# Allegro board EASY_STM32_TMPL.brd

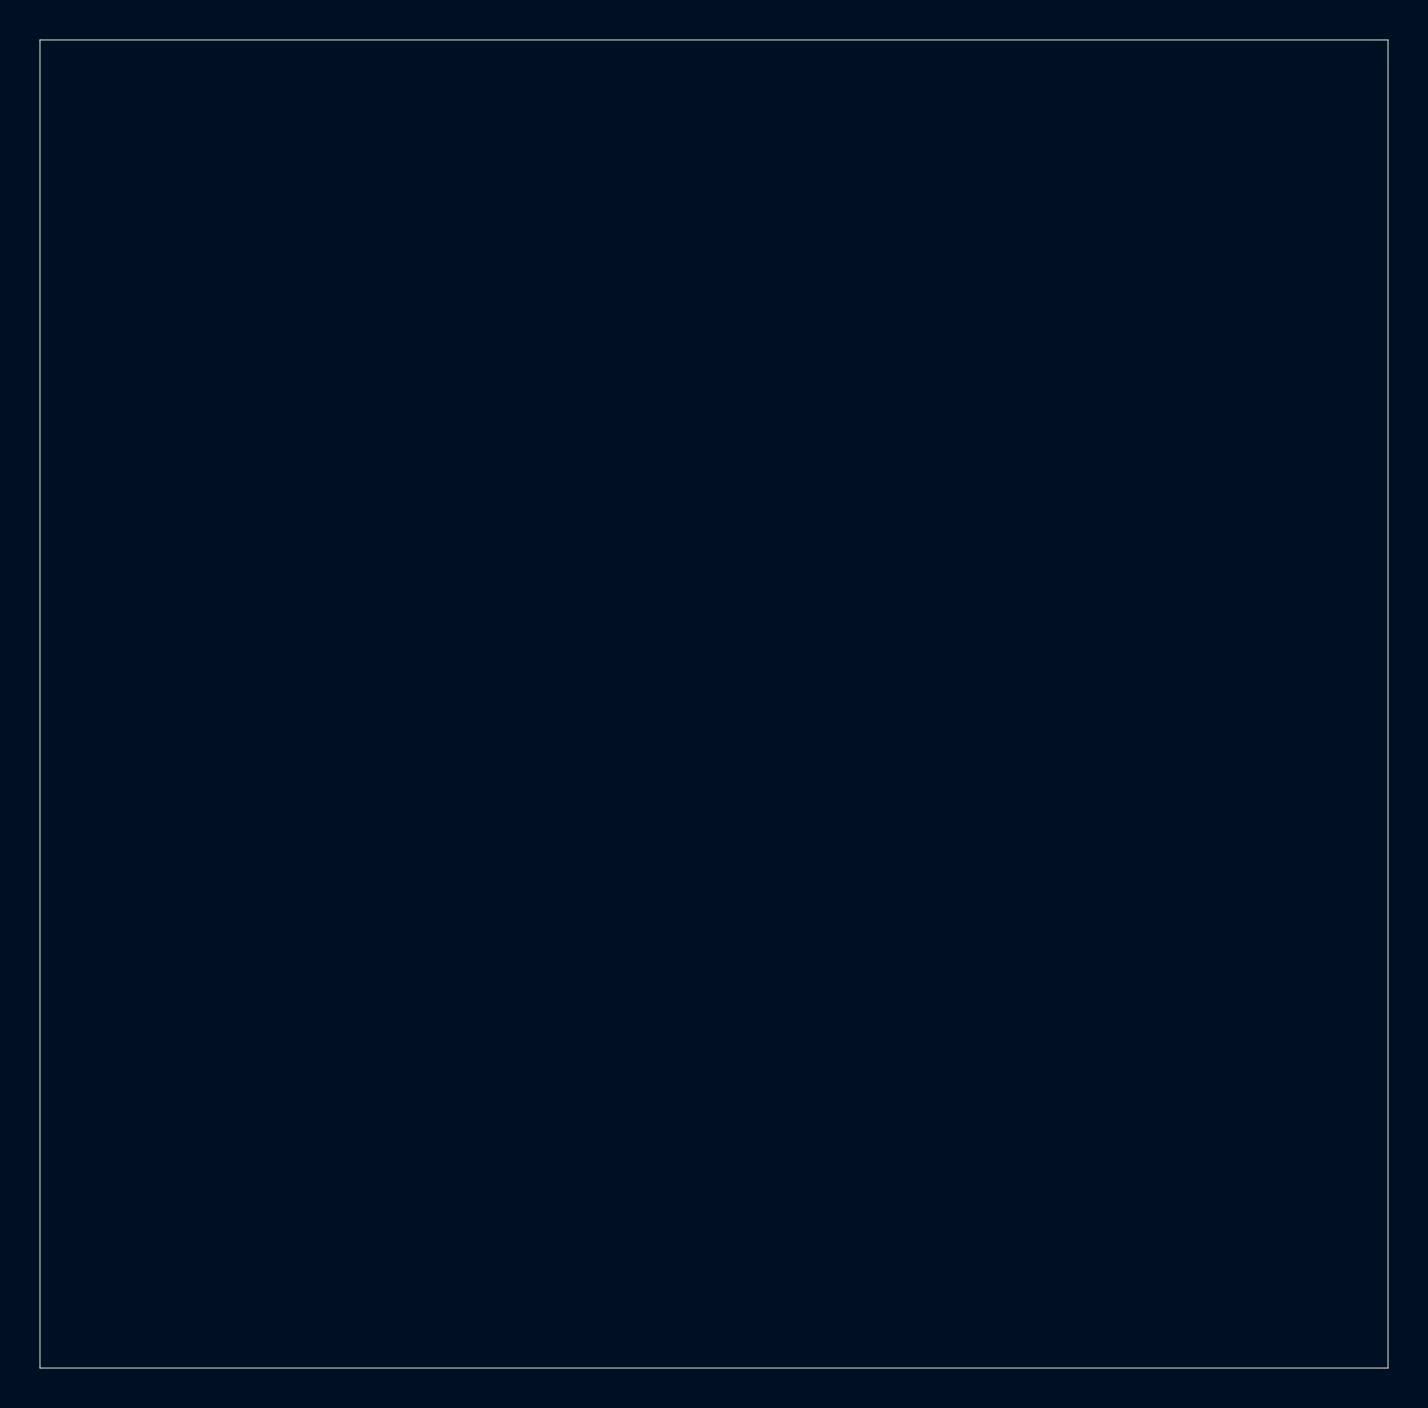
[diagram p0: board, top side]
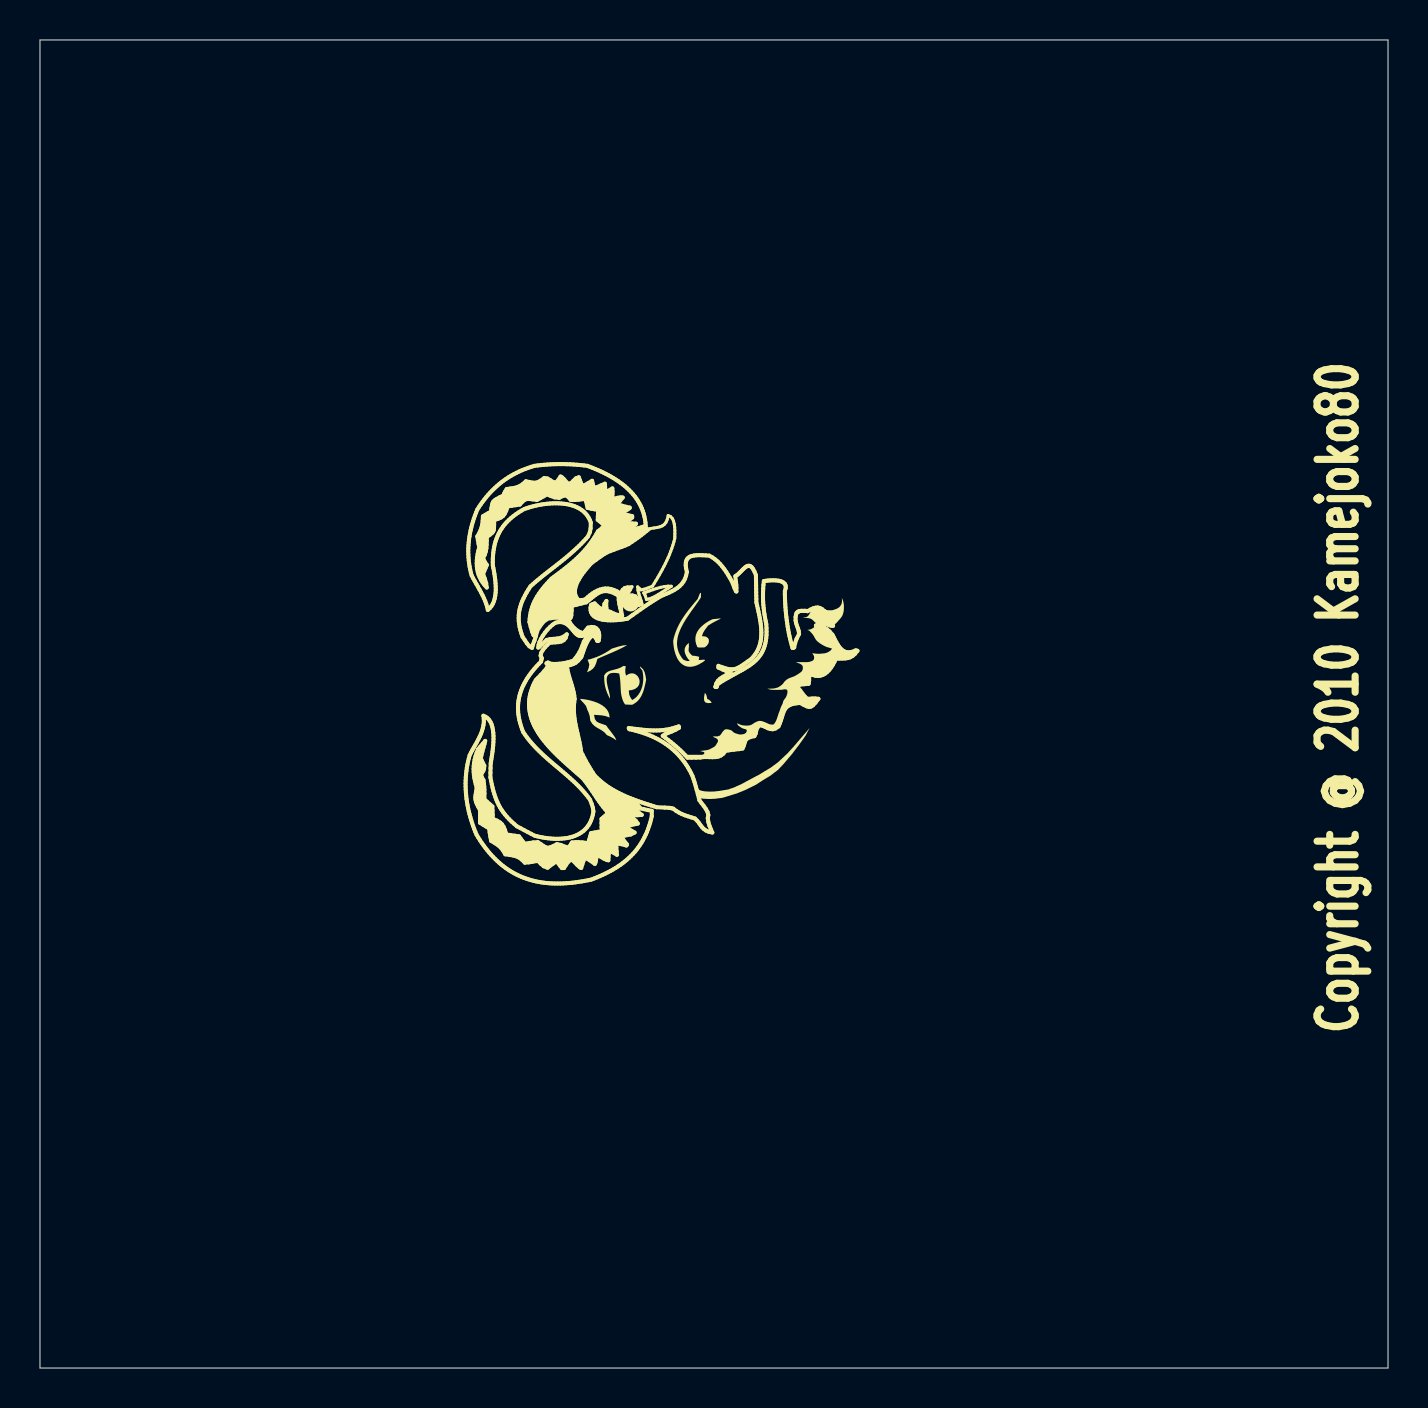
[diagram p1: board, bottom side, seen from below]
Outline 67.44 x 66.42 mm; copper layers: TOP, BOTTOM. Coordinates in mm from the lower left corner of the outline.
Outline path: 0,66.42 0,0 67.44,0 67.44,66.42 0,66.42

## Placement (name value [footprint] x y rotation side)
NOREF  -  []  25.27 25.27 90 bottom

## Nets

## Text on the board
Ref Des/Silkscreen Bottom: Copyright @ 2010 Kamejoko80
NCLEGEND-1-2: FIGURE | SIZE | 0.508 | 0.8 | 0.8999 | 0.9144 | 1.0 | 2.4 | DRILL CHART: TOP to BOTTOM | ALL UNITS ARE IN MILLIMETERS | PLATED | QTY | 121 | 14 | 200 | 2 | 4
